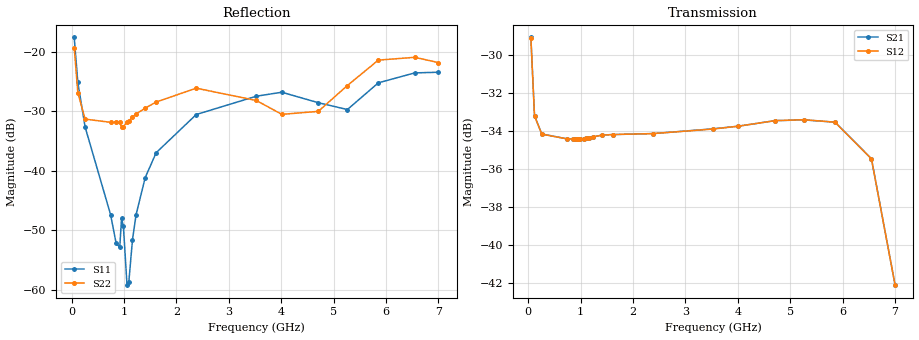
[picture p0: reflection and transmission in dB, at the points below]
! Integrated Device Technology
! Corporate Headquarters
! 6024 Silver Creek Valley Road
! San Jose, CA 95138  USA
! Phone:  1-408-284-8200
! Toll Free:  1-800-223-1366
! Webpage:  http://www.idt.com/
! Timing and RF Division
! 515 Groton Road, Suite 102
! Westford, MA 01886-6024
! Device:  F2258
! Description: Voltage Variable RF Attenuator
! Frequency:  50.0 -  6000.00 MHz
! Package:  3x3 mm Thin QFN Plastic Package: 16 pin
! Ports:  2 RF, 2 DC
!  Pin  1  = NC
!  Pin  2  = NC
!  Pin  3  = RF2  = Port 2
!  Pin  4  = GND
!  Pin  5  = Vdd
!  Pin  6  = NC
!  Pin  7  = VCTRL
!  Pin  8  = NC
!  Pin  9  = GND
!  Pin 10  = RF1  = Port 1
!  Pin 11  = NC
!  Pin 12  = NC
!  Pin 13  = NC
!  Pin 14  = NC
!  Pin 15  = NC
!  Pin 16  = NC
! Vcntrl:  1.890 Volts
! Vdd:  +3.300 Volts
! Current:  1.157 mA
! Data:  The device was measured on a the F2258 evaluation board which has
!  individual transmission lines to the RF pins.  Data was collected
!  using a calibrated network analyzer.  The evaluation board was
!  de-embedded using a TRL calibration technique.
!  The reference plane is the edge of the package pin.
! Misc:  SN 10
!  Action Tracker AT0285
! Date Measured:  2014-12-10
! Date:  2016-01-13  MJV
! Note:
!  Integrated Device Technology supplies this data as a sample of measured
!  data at the package pin for this product.  Your particular data for this
!  product may vary.
!  Data was taken at 25 degrees C.
!  Integrated Device Technology reserves the right to change this data at anytime.
!Freq_(GHz)  S11M_(dB)  S11P_(deg)  S21M_(dB)  S21P_(deg)  S12M_(dB)  S12P_(deg)  S22M_(dB)  S22P_(deg)
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# GHz S dB R 50
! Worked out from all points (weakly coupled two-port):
!   201 points, 50 MHz to 7 GHz, reference 50 ohm
!   highest |S21| = -29.09 dB at 50 MHz (marker M1); lowest = -42.1 dB at 7 GHz (marker M2)
!   lowest |S11| = -59.2 dB at 1.058 GHz (marker M3), VSWR 1.00, Z = 49.9 + j0.0516 ohm
!   |S11| at or under -10 dB: start of sweep to end of sweep
!   |S22| runs from -32.7 to -19.3 dB; largest |S21 - S12| = 4.7e-05
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0.05  -17.55 -110.8  -29.09 -64.4  -29.10 -64.4  -19.27 -103.1
0.1195  -25.12 -106.6  -33.21 -34.2  -33.22 -34.2  -26.87 -74.1
0.2585  -32.63 -111.3  -34.17 -17.7  -34.18 -17.7  -31.29 -40.1
0.745  -47.38 -141.3  -34.43 -9.3  -34.43 -9.3  -31.83 -2.5
0.84925  -52.14 -171.7  -34.43 -9.0  -34.43 -9.0  -31.77 -0.1
0.91875  -52.85 149.3  -34.43 -8.9  -34.42 -8.9  -31.81 0.1
0.9535  -47.98 -160.5  -34.44 -8.9  -34.44 -8.9  -32.69 5.9
0.98825  -49.24 -172.9  -34.42 -8.8  -34.42 -8.8  -32.55 4.7
1.05775  -59.20 151.9  -34.41 -8.8  -34.41 -8.8  -31.81 5.4
1.0925  -58.64 113.1  -34.40 -8.7  -34.39 -8.7  -31.61 5.5
1.162  -51.56 65.1  -34.36 -8.8  -34.36 -8.8  -30.95 5.6
1.2315  -47.33 43.6  -34.33 -8.9  -34.33 -8.9  -30.42 5.6
1.40525  -41.11 32.4  -34.23 -9.7  -34.23 -9.7  -29.44 7.2
1.61375  -36.94 32.0  -34.20 -10.9  -34.20 -11.0  -28.42 5.7
2.37825  -30.52 47.7  -34.15 -15.1  -34.15 -15.0  -26.09 8.5
3.525  -27.44 91.4  -33.90 -22.2  -33.91 -22.2  -28.16 28.9
4.0115  -26.77 104.4  -33.76 -26.0  -33.76 -26.0  -30.49 37.1
4.7065  -28.53 95.5  -33.47 -31.8  -33.47 -31.7  -29.99 16.6
5.2625  -29.68 54.0  -33.43 -37.9  -33.42 -37.8  -25.64 -10.1
5.85325  -25.19 29.6  -33.55 -48.0  -33.55 -48.1  -21.37 -21.1
6.54825  -23.52 44.9  -35.47 -67.3  -35.48 -67.3  -20.90 -52.0
7  -23.41 84.4  -42.12 -63.8  -42.12 -63.5  -21.79 -125.6
